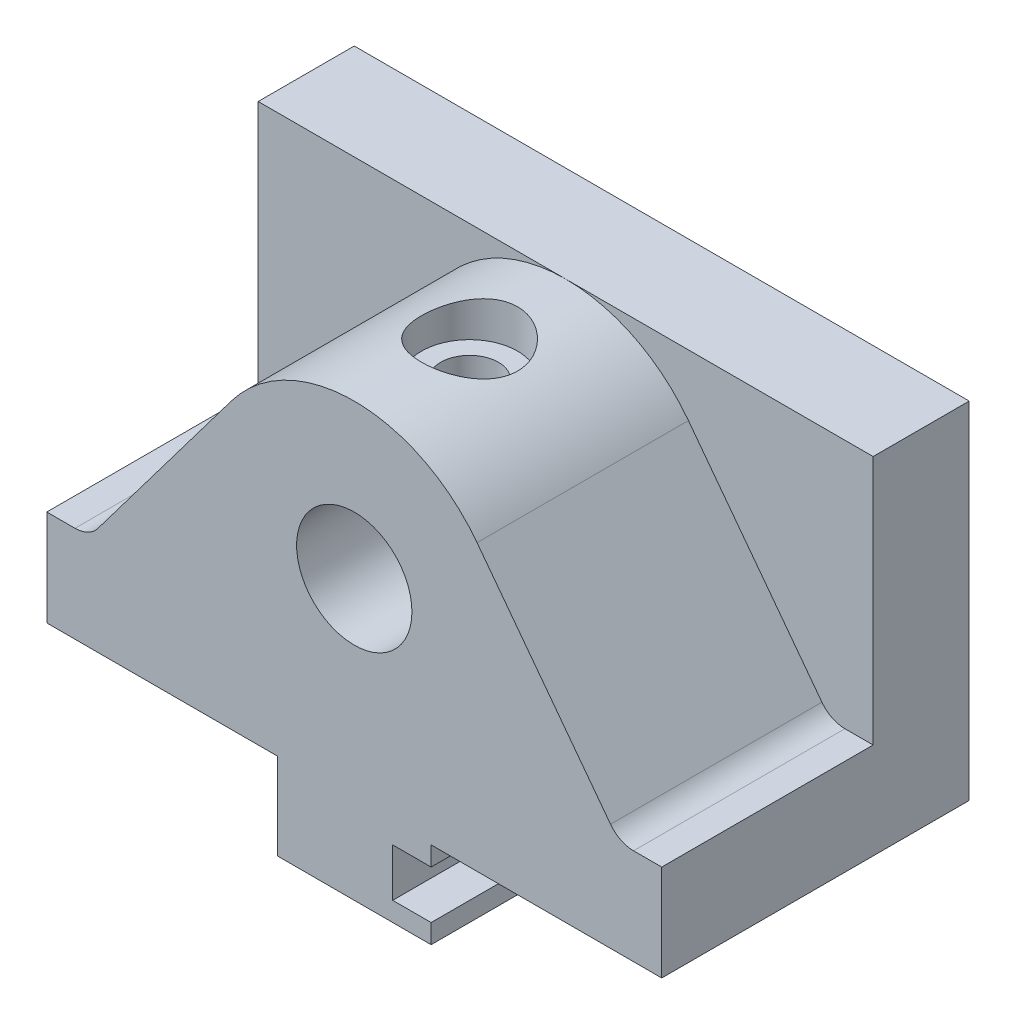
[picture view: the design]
ISO-10303-21;
HEADER;
FILE_DESCRIPTION(('STEP AP214'),'2;1');
FILE_NAME('part.step','',(''),(''),'','','');
FILE_SCHEMA(('AUTOMOTIVE_DESIGN { 1 0 10303 214 1 1 1 1 }'));
ENDSEC;
DATA;
#1=APPLICATION_CONTEXT('core data for automotive mechanical design processes');
#2=APPLICATION_PROTOCOL_DEFINITION('international standard','automotive_design',2000,#1);
#3=PRODUCT_CONTEXT('',#1,'mechanical');
#4=PRODUCT('Part','Part','',(#3));
#5=PRODUCT_RELATED_PRODUCT_CATEGORY('part','',(#4));
#6=PRODUCT_DEFINITION_FORMATION('','',#4);
#7=PRODUCT_DEFINITION_CONTEXT('part definition',#1,'design');
#8=PRODUCT_DEFINITION('design','',#6,#7);
#9=PRODUCT_DEFINITION_SHAPE('','',#8);
#10=(LENGTH_UNIT() NAMED_UNIT(*) SI_UNIT(.MILLI.,.METRE.));
#11=(NAMED_UNIT(*) PLANE_ANGLE_UNIT() SI_UNIT($,.RADIAN.));
#12=(NAMED_UNIT(*) SI_UNIT($,.STERADIAN.) SOLID_ANGLE_UNIT());
#13=UNCERTAINTY_MEASURE_WITH_UNIT(LENGTH_MEASURE(1.E-05),#10,'distance_accuracy_value','');
#14=(GEOMETRIC_REPRESENTATION_CONTEXT(3) GLOBAL_UNCERTAINTY_ASSIGNED_CONTEXT((#13)) GLOBAL_UNIT_ASSIGNED_CONTEXT((#10,
#11,#12)) REPRESENTATION_CONTEXT('',''));
#15=CARTESIAN_POINT('',(0.,0.,0.));
#16=DIRECTION('',(0.,0.,1.));
#17=DIRECTION('',(1.,0.,0.));
#18=AXIS2_PLACEMENT_3D('',#15,#16,#17);
#19=CARTESIAN_POINT('',(8.,-9.,22.));
#20=DIRECTION('',(-1.,0.,0.));
#21=DIRECTION('',(0.,-1.,0.));
#22=AXIS2_PLACEMENT_3D('',#19,#20,#21);
#23=PLANE('',#22);
#24=DIRECTION('',(0.,-1.,0.));
#25=VECTOR('',#24,1.);
#26=CARTESIAN_POINT('',(7.99999999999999,-9.,-9.99999999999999));
#27=LINE('',#26,#25);
#28=CARTESIAN_POINT('',(7.99999999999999,-7.,-9.99999999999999));
#29=VERTEX_POINT('',#28);
#30=CARTESIAN_POINT('',(7.99999999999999,-9.,-9.99999999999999));
#31=VERTEX_POINT('',#30);
#32=EDGE_CURVE('E212',#29,#31,#27,.T.);
#33=ORIENTED_EDGE('',*,*,#32,.F.);
#34=DIRECTION('',(0.,0.,1.));
#35=VECTOR('',#34,1.);
#36=CARTESIAN_POINT('',(7.99999999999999,-7.,-9.99999999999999));
#37=LINE('',#36,#35);
#38=CARTESIAN_POINT('',(8.,-7.,22.));
#39=VERTEX_POINT('',#38);
#40=EDGE_CURVE('E439',#29,#39,#37,.T.);
#41=ORIENTED_EDGE('',*,*,#40,.T.);
#42=DIRECTION('',(0.,1.,0.));
#43=VECTOR('',#42,1.);
#44=CARTESIAN_POINT('',(8.,-9.,22.));
#45=LINE('',#44,#43);
#46=CARTESIAN_POINT('',(8.,-9.,22.));
#47=VERTEX_POINT('',#46);
#48=EDGE_CURVE('E250',#47,#39,#45,.T.);
#49=ORIENTED_EDGE('',*,*,#48,.F.);
#50=DIRECTION('',(0.,0.,-1.));
#51=VECTOR('',#50,1.);
#52=CARTESIAN_POINT('',(8.,-9.,22.));
#53=LINE('',#52,#51);
#54=EDGE_CURVE('E358',#47,#31,#53,.T.);
#55=ORIENTED_EDGE('',*,*,#54,.T.);
#56=EDGE_LOOP('',(#33,#41,#49,#55));
#57=FACE_BOUND('',#56,.T.);
#58=ADVANCED_FACE('F34',(#57),#23,.F.);
#59=CARTESIAN_POINT('',(-8.,0.,22.));
#60=DIRECTION('',(1.,0.,0.));
#61=DIRECTION('',(0.,1.,0.));
#62=AXIS2_PLACEMENT_3D('',#59,#60,#61);
#63=PLANE('',#62);
#64=DIRECTION('',(0.,0.,-1.));
#65=VECTOR('',#64,1.);
#66=CARTESIAN_POINT('',(-8.,0.,22.));
#67=LINE('',#66,#65);
#68=CARTESIAN_POINT('',(-8.,0.,22.));
#69=VERTEX_POINT('',#68);
#70=CARTESIAN_POINT('',(-8.,0.,-10.));
#71=VERTEX_POINT('',#70);
#72=EDGE_CURVE('E272',#69,#71,#67,.T.);
#73=ORIENTED_EDGE('',*,*,#72,.T.);
#74=DIRECTION('',(0.,1.,0.));
#75=VECTOR('',#74,1.);
#76=CARTESIAN_POINT('',(-8.,0.,-10.));
#77=LINE('',#76,#75);
#78=CARTESIAN_POINT('',(-8.00000000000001,-9.,-10.));
#79=VERTEX_POINT('',#78);
#80=EDGE_CURVE('E215',#79,#71,#77,.T.);
#81=ORIENTED_EDGE('',*,*,#80,.F.);
#82=DIRECTION('',(0.,0.,-1.));
#83=VECTOR('',#82,1.);
#84=CARTESIAN_POINT('',(-8.,-9.,22.));
#85=LINE('',#84,#83);
#86=CARTESIAN_POINT('',(-8.,-9.,22.));
#87=VERTEX_POINT('',#86);
#88=EDGE_CURVE('E295',#87,#79,#85,.T.);
#89=ORIENTED_EDGE('',*,*,#88,.F.);
#90=DIRECTION('',(0.,-1.,0.));
#91=VECTOR('',#90,1.);
#92=CARTESIAN_POINT('',(-8.,0.,22.));
#93=LINE('',#92,#91);
#94=EDGE_CURVE('E244',#69,#87,#93,.T.);
#95=ORIENTED_EDGE('',*,*,#94,.F.);
#96=EDGE_LOOP('',(#73,#81,#89,#95));
#97=FACE_BOUND('',#96,.T.);
#98=ADVANCED_FACE('F372',(#97),#63,.F.);
#99=CARTESIAN_POINT('',(-8.,-9.,22.));
#100=DIRECTION('',(0.,1.,0.));
#101=DIRECTION('',(0.,0.,1.));
#102=AXIS2_PLACEMENT_3D('',#99,#100,#101);
#103=PLANE('',#102);
#104=CARTESIAN_POINT('',(0.,-9.,14.));
#105=DIRECTION('',(0.,-1.,0.));
#106=DIRECTION('',(0.,0.,-1.));
#107=AXIS2_PLACEMENT_3D('',#104,#105,#106);
#108=CIRCLE('',#107,2.99999999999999);
#109=CARTESIAN_POINT('',(0.,-9.,11.));
#110=VERTEX_POINT('',#109);
#111=EDGE_CURVE('E463',#110,#110,#108,.T.);
#112=ORIENTED_EDGE('',*,*,#111,.F.);
#113=EDGE_LOOP('',(#112));
#114=FACE_BOUND('',#113,.T.);
#115=CARTESIAN_POINT('',(0.,-9.,-2.));
#116=DIRECTION('',(0.,-1.,0.));
#117=DIRECTION('',(0.,0.,-1.));
#118=AXIS2_PLACEMENT_3D('',#115,#116,#117);
#119=CIRCLE('',#118,2.99999999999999);
#120=CARTESIAN_POINT('',(0.,-9.,-4.99999999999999));
#121=VERTEX_POINT('',#120);
#122=EDGE_CURVE('E740',#121,#121,#119,.T.);
#123=ORIENTED_EDGE('',*,*,#122,.F.);
#124=EDGE_LOOP('',(#123));
#125=FACE_BOUND('',#124,.T.);
#126=ORIENTED_EDGE('',*,*,#88,.T.);
#127=DIRECTION('',(-1.,0.,0.));
#128=VECTOR('',#127,1.);
#129=CARTESIAN_POINT('',(-8.00000000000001,-9.,-10.));
#130=LINE('',#129,#128);
#131=EDGE_CURVE('E211',#31,#79,#130,.T.);
#132=ORIENTED_EDGE('',*,*,#131,.F.);
#133=ORIENTED_EDGE('',*,*,#54,.F.);
#134=DIRECTION('',(1.,0.,0.));
#135=VECTOR('',#134,1.);
#136=CARTESIAN_POINT('',(-8.,-9.,22.));
#137=LINE('',#136,#135);
#138=EDGE_CURVE('E247',#87,#47,#137,.T.);
#139=ORIENTED_EDGE('',*,*,#138,.F.);
#140=EDGE_LOOP('',(#126,#132,#133,#139));
#141=FACE_BOUND('',#140,.T.);
#142=ADVANCED_FACE('F367',(#114,#125,#141),#103,.F.);
#143=CARTESIAN_POINT('',(8.,-2.,22.));
#144=VERTEX_POINT('',#143);
#145=CARTESIAN_POINT('',(8.00000000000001,0.,22.));
#146=VERTEX_POINT('',#145);
#147=EDGE_CURVE('E204',#144,#146,#45,.T.);
#148=ORIENTED_EDGE('',*,*,#147,.F.);
#149=DIRECTION('',(0.,0.,1.));
#150=VECTOR('',#149,1.);
#151=CARTESIAN_POINT('',(7.99999999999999,-2.,-9.99999999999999));
#152=LINE('',#151,#150);
#153=CARTESIAN_POINT('',(7.99999999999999,-2.,-9.99999999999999));
#154=VERTEX_POINT('',#153);
#155=EDGE_CURVE('E190',#154,#144,#152,.T.);
#156=ORIENTED_EDGE('',*,*,#155,.F.);
#157=CARTESIAN_POINT('',(8.00000000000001,0.,-9.99999999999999));
#158=VERTEX_POINT('',#157);
#159=EDGE_CURVE('E202',#158,#154,#27,.T.);
#160=ORIENTED_EDGE('',*,*,#159,.F.);
#161=DIRECTION('',(0.,0.,-1.));
#162=VECTOR('',#161,1.);
#163=CARTESIAN_POINT('',(8.00000000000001,0.,22.));
#164=LINE('',#163,#162);
#165=EDGE_CURVE('E357',#146,#158,#164,.T.);
#166=ORIENTED_EDGE('',*,*,#165,.F.);
#167=EDGE_LOOP('',(#148,#156,#160,#166));
#168=FACE_BOUND('',#167,.T.);
#169=ADVANCED_FACE('F200',(#168),#23,.F.);
#170=CARTESIAN_POINT('',(8.00000000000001,0.,22.));
#171=DIRECTION('',(0.,1.,0.));
#172=DIRECTION('',(0.,0.,1.));
#173=AXIS2_PLACEMENT_3D('',#170,#171,#172);
#174=PLANE('',#173);
#175=ORIENTED_EDGE('',*,*,#165,.T.);
#176=DIRECTION('',(-1.,0.,0.));
#177=VECTOR('',#176,1.);
#178=CARTESIAN_POINT('',(8.00000000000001,0.,-9.99999999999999));
#179=LINE('',#178,#177);
#180=CARTESIAN_POINT('',(32.,0.,-9.99999999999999));
#181=VERTEX_POINT('',#180);
#182=EDGE_CURVE('E210',#181,#158,#179,.T.);
#183=ORIENTED_EDGE('',*,*,#182,.F.);
#184=DIRECTION('',(0.,0.,-1.));
#185=VECTOR('',#184,1.);
#186=CARTESIAN_POINT('',(32.,0.,22.));
#187=LINE('',#186,#185);
#188=CARTESIAN_POINT('',(32.,0.,22.));
#189=VERTEX_POINT('',#188);
#190=EDGE_CURVE('E339',#189,#181,#187,.T.);
#191=ORIENTED_EDGE('',*,*,#190,.F.);
#192=DIRECTION('',(1.,0.,0.));
#193=VECTOR('',#192,1.);
#194=CARTESIAN_POINT('',(8.00000000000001,0.,22.));
#195=LINE('',#194,#193);
#196=EDGE_CURVE('E253',#146,#189,#195,.T.);
#197=ORIENTED_EDGE('',*,*,#196,.F.);
#198=EDGE_LOOP('',(#175,#183,#191,#197));
#199=FACE_BOUND('',#198,.T.);
#200=ADVANCED_FACE('F390',(#199),#174,.F.);
#201=CARTESIAN_POINT('',(32.,0.,22.));
#202=DIRECTION('',(-1.,0.,0.));
#203=DIRECTION('',(0.,0.,1.));
#204=AXIS2_PLACEMENT_3D('',#201,#202,#203);
#205=PLANE('',#204);
#206=ORIENTED_EDGE('',*,*,#190,.T.);
#207=DIRECTION('',(0.,-1.,0.));
#208=VECTOR('',#207,1.);
#209=CARTESIAN_POINT('',(32.,36.,-9.99999999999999));
#210=LINE('',#209,#208);
#211=CARTESIAN_POINT('',(32.,36.,-9.99999999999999));
#212=VERTEX_POINT('',#211);
#213=EDGE_CURVE('E229',#212,#181,#210,.T.);
#214=ORIENTED_EDGE('',*,*,#213,.F.);
#215=DIRECTION('',(0.,0.,1.));
#216=VECTOR('',#215,1.);
#217=CARTESIAN_POINT('',(32.,36.,-9.99999999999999));
#218=LINE('',#217,#216);
#219=CARTESIAN_POINT('',(32.,36.,0.));
#220=VERTEX_POINT('',#219);
#221=EDGE_CURVE('E231',#212,#220,#218,.T.);
#222=ORIENTED_EDGE('',*,*,#221,.T.);
#223=DIRECTION('',(0.,-1.,0.));
#224=VECTOR('',#223,1.);
#225=CARTESIAN_POINT('',(32.,0.,0.));
#226=LINE('',#225,#224);
#227=CARTESIAN_POINT('',(32.,10.,0.));
#228=VERTEX_POINT('',#227);
#229=EDGE_CURVE('E242',#220,#228,#226,.T.);
#230=ORIENTED_EDGE('',*,*,#229,.T.);
#231=DIRECTION('',(0.,0.,-1.));
#232=VECTOR('',#231,1.);
#233=CARTESIAN_POINT('',(32.,10.,22.));
#234=LINE('',#233,#232);
#235=CARTESIAN_POINT('',(32.,10.,22.));
#236=VERTEX_POINT('',#235);
#237=EDGE_CURVE('E329',#236,#228,#234,.T.);
#238=ORIENTED_EDGE('',*,*,#237,.F.);
#239=DIRECTION('',(0.,1.,0.));
#240=VECTOR('',#239,1.);
#241=CARTESIAN_POINT('',(32.,0.,22.));
#242=LINE('',#241,#240);
#243=EDGE_CURVE('E255',#189,#236,#242,.T.);
#244=ORIENTED_EDGE('',*,*,#243,.F.);
#245=EDGE_LOOP('',(#206,#214,#222,#230,#238,#244));
#246=FACE_BOUND('',#245,.T.);
#247=ADVANCED_FACE('F394',(#246),#205,.F.);
#248=CARTESIAN_POINT('',(32.,10.,22.));
#249=DIRECTION('',(0.,-1.,0.));
#250=DIRECTION('',(1.,0.,0.));
#251=AXIS2_PLACEMENT_3D('',#248,#249,#250);
#252=PLANE('',#251);
#253=DIRECTION('',(-1.,0.,0.));
#254=VECTOR('',#253,1.);
#255=CARTESIAN_POINT('',(32.,10.,0.));
#256=LINE('',#255,#254);
#257=CARTESIAN_POINT('',(29.0654558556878,9.99999999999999,0.));
#258=VERTEX_POINT('',#257);
#259=EDGE_CURVE('E276',#228,#258,#256,.T.);
#260=ORIENTED_EDGE('',*,*,#259,.T.);
#261=DIRECTION('',(0.,0.,-1.));
#262=VECTOR('',#261,1.);
#263=CARTESIAN_POINT('',(29.0654558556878,9.99999999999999,22.));
#264=LINE('',#263,#262);
#265=CARTESIAN_POINT('',(29.0654558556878,9.99999999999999,22.));
#266=VERTEX_POINT('',#265);
#267=EDGE_CURVE('E62',#258,#266,#264,.F.);
#268=ORIENTED_EDGE('',*,*,#267,.T.);
#269=DIRECTION('',(-1.,0.,0.));
#270=VECTOR('',#269,1.);
#271=CARTESIAN_POINT('',(32.,10.,22.));
#272=LINE('',#271,#270);
#273=EDGE_CURVE('E257',#236,#266,#272,.T.);
#274=ORIENTED_EDGE('',*,*,#273,.F.);
#275=ORIENTED_EDGE('',*,*,#237,.T.);
#276=EDGE_LOOP('',(#260,#268,#274,#275));
#277=FACE_BOUND('',#276,.T.);
#278=ADVANCED_FACE('F327',(#277),#252,.F.);
#279=CARTESIAN_POINT('',(27.5697110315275,9.99999999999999,22.));
#280=DIRECTION('',(-0.798635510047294,-0.601815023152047,0.));
#281=DIRECTION('',(0.601815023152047,-0.798635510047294,0.));
#282=AXIS2_PLACEMENT_3D('',#279,#280,#281);
#283=PLANE('',#282);
#284=DIRECTION('',(-0.601815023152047,0.798635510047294,0.));
#285=VECTOR('',#284,1.);
#286=CARTESIAN_POINT('',(27.5697110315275,9.99999999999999,22.));
#287=LINE('',#286,#285);
#288=CARTESIAN_POINT('',(26.6695493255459,11.1945549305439,22.));
#289=VERTEX_POINT('',#288);
#290=CARTESIAN_POINT('',(12.7781681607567,29.6290403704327,22.));
#291=VERTEX_POINT('',#290);
#292=EDGE_CURVE('E259',#289,#291,#287,.T.);
#293=ORIENTED_EDGE('',*,*,#292,.F.);
#294=DIRECTION('',(0.,0.,-1.));
#295=VECTOR('',#294,1.);
#296=CARTESIAN_POINT('',(26.6695493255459,11.1945549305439,0.));
#297=LINE('',#296,#295);
#298=CARTESIAN_POINT('',(26.6695493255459,11.1945549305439,0.));
#299=VERTEX_POINT('',#298);
#300=EDGE_CURVE('E299',#289,#299,#297,.T.);
#301=ORIENTED_EDGE('',*,*,#300,.T.);
#302=DIRECTION('',(-0.601815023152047,0.798635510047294,0.));
#303=VECTOR('',#302,1.);
#304=CARTESIAN_POINT('',(27.5697110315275,9.99999999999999,0.));
#305=LINE('',#304,#303);
#306=CARTESIAN_POINT('',(12.7781681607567,29.6290403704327,0.));
#307=VERTEX_POINT('',#306);
#308=EDGE_CURVE('E273',#299,#307,#305,.T.);
#309=ORIENTED_EDGE('',*,*,#308,.T.);
#310=DIRECTION('',(0.,0.,-1.));
#311=VECTOR('',#310,1.);
#312=CARTESIAN_POINT('',(12.7781681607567,29.6290403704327,22.));
#313=LINE('',#312,#311);
#314=EDGE_CURVE('E319',#291,#307,#313,.T.);
#315=ORIENTED_EDGE('',*,*,#314,.F.);
#316=EDGE_LOOP('',(#293,#301,#309,#315));
#317=FACE_BOUND('',#316,.T.);
#318=ADVANCED_FACE('F316',(#317),#283,.F.);
#319=CARTESIAN_POINT('',(0.,20.,22.));
#320=DIRECTION('',(0.,0.,-1.));
#321=DIRECTION('',(-1.,0.,0.));
#322=AXIS2_PLACEMENT_3D('',#319,#320,#321);
#323=CYLINDRICAL_SURFACE('',#322,16.);
#324=CARTESIAN_POINT('',(0.,36.,15.));
#325=CARTESIAN_POINT('',(-0.273756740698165,35.9999986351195,14.9999982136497));
#326=CARTESIAN_POINT('',(-0.547532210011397,35.9929077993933,14.9774430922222));
#327=CARTESIAN_POINT('',(-1.08707683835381,35.9653157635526,14.888055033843));
#328=CARTESIAN_POINT('',(-1.35284417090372,35.9448115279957,14.8212120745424));
#329=CARTESIAN_POINT('',(-1.86851417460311,35.892632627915,14.6457225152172));
#330=CARTESIAN_POINT('',(-2.11844070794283,35.860975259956,14.5371406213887));
#331=CARTESIAN_POINT('',(-2.59653920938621,35.7897587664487,14.2815307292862));
#332=CARTESIAN_POINT('',(-2.82470774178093,35.7501983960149,14.1344966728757));
#333=CARTESIAN_POINT('',(-3.25986133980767,35.6660085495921,13.8013760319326));
#334=CARTESIAN_POINT('',(-3.46608011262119,35.621268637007,13.6143164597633));
#335=CARTESIAN_POINT('',(-3.84478952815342,35.5324018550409,13.2085264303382));
#336=CARTESIAN_POINT('',(-4.01727389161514,35.4882751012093,12.9897900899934));
#337=CARTESIAN_POINT('',(-4.32777345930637,35.4044457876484,12.5202217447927));
#338=CARTESIAN_POINT('',(-4.4648313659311,35.364879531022,12.2687300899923));
#339=CARTESIAN_POINT('',(-4.69438964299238,35.2963120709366,11.7448307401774));
#340=CARTESIAN_POINT('',(-4.78690175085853,35.2673080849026,11.4724285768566));
#341=CARTESIAN_POINT('',(-4.92193839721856,35.224304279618,10.9230876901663));
#342=CARTESIAN_POINT('',(-4.96588440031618,35.2098789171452,10.6465326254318));
#343=CARTESIAN_POINT('',(-5.00698220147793,35.1964022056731,10.0896275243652));
#344=CARTESIAN_POINT('',(-5.00414643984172,35.1973467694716,9.80927851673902));
#345=CARTESIAN_POINT('',(-4.95287298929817,35.2141275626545,9.26450215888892));
#346=CARTESIAN_POINT('',(-4.90624231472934,35.2293736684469,8.99988349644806));
#347=CARTESIAN_POINT('',(-4.7716325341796,35.272081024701,8.48243137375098));
#348=CARTESIAN_POINT('',(-4.68364903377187,35.2995435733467,8.22959916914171));
#349=CARTESIAN_POINT('',(-4.46755498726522,35.3640417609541,7.73859222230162));
#350=CARTESIAN_POINT('',(-4.33887702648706,35.4012113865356,7.5006855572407));
#351=CARTESIAN_POINT('',(-4.04544082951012,35.4808742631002,7.04924892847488));
#352=CARTESIAN_POINT('',(-3.88067322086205,35.523368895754,6.83572531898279));
#353=CARTESIAN_POINT('',(-3.51086781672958,35.6112611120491,6.42890022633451));
#354=CARTESIAN_POINT('',(-3.30433828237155,35.6567027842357,6.23696176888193));
#355=CARTESIAN_POINT('',(-2.86145763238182,35.7436628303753,5.89011242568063));
#356=CARTESIAN_POINT('',(-2.625104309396,35.7851809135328,5.735204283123));
#357=CARTESIAN_POINT('',(-2.12665844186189,35.8600517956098,5.46588924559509));
#358=CARTESIAN_POINT('',(-1.86437962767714,35.8933384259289,5.35180745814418));
#359=CARTESIAN_POINT('',(-1.32307191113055,35.9475182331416,5.1697879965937));
#360=CARTESIAN_POINT('',(-1.04404812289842,35.9684151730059,5.10183631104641));
#361=CARTESIAN_POINT('',(-0.488740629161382,35.9948555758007,5.0163278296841));
#362=CARTESIAN_POINT('',(-0.212767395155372,36.0009609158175,4.99692582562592));
#363=CARTESIAN_POINT('',(0.338521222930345,35.9987919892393,5.00386490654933));
#364=CARTESIAN_POINT('',(0.613836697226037,35.9905198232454,5.03019930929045));
#365=CARTESIAN_POINT('',(1.14887733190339,35.9608945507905,5.12638237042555));
#366=CARTESIAN_POINT('',(1.40881991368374,35.9398717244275,5.19513307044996));
#367=CARTESIAN_POINT('',(1.9134077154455,35.8872048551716,5.37285740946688));
#368=CARTESIAN_POINT('',(2.15805104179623,35.8555595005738,5.48183601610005));
#369=CARTESIAN_POINT('',(2.63172962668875,35.783941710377,5.73989286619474));
#370=CARTESIAN_POINT('',(2.86023895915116,35.7437850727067,5.88988394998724));
#371=CARTESIAN_POINT('',(3.28946340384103,35.6597364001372,6.22461284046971));
#372=CARTESIAN_POINT('',(3.49017095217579,35.6158433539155,6.40936007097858));
#373=CARTESIAN_POINT('',(3.86634985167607,35.5270797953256,6.8170355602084));
#374=CARTESIAN_POINT('',(4.04050609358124,35.4822394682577,7.0411866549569));
#375=CARTESIAN_POINT('',(4.34885000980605,35.3984778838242,7.51650646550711));
#376=CARTESIAN_POINT('',(4.48303831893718,35.3595565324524,7.76767475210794));
#377=CARTESIAN_POINT('',(4.70680333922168,35.2924712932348,8.28938069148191));
#378=CARTESIAN_POINT('',(4.79655278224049,35.264265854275,8.55983859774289));
#379=CARTESIAN_POINT('',(4.9289157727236,35.2220468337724,9.11308997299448));
#380=CARTESIAN_POINT('',(4.97154725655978,35.2080278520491,9.39587870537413));
#381=CARTESIAN_POINT('',(5.00717624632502,35.1963317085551,9.95201635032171));
#382=CARTESIAN_POINT('',(5.00233118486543,35.1979441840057,10.2252138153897));
#383=CARTESIAN_POINT('',(4.94835272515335,35.2156036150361,10.7666983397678));
#384=CARTESIAN_POINT('',(4.89922139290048,35.2316498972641,11.0349856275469));
#385=CARTESIAN_POINT('',(4.7595091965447,35.2758725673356,11.5551761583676));
#386=CARTESIAN_POINT('',(4.66954569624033,35.3038679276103,11.8072617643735));
#387=CARTESIAN_POINT('',(4.45120909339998,35.3687881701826,12.292961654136));
#388=CARTESIAN_POINT('',(4.32282817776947,35.4057148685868,12.5265721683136));
#389=CARTESIAN_POINT('',(4.02542700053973,35.4861394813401,12.9785838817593));
#390=CARTESIAN_POINT('',(3.85501334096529,35.5298379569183,13.196032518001));
#391=CARTESIAN_POINT('',(3.4808359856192,35.6179599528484,13.599945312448));
#392=CARTESIAN_POINT('',(3.27706336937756,35.6623836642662,13.7864011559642));
#393=CARTESIAN_POINT('',(2.83394665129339,35.7486908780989,14.1291301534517));
#394=CARTESIAN_POINT('',(2.59365829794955,35.7904440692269,14.2842189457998));
#395=CARTESIAN_POINT('',(2.08911655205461,35.8650707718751,14.5515956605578));
#396=CARTESIAN_POINT('',(1.8248726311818,35.8979477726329,14.6639004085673));
#397=CARTESIAN_POINT('',(1.30299054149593,35.9488260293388,14.8343654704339));
#398=CARTESIAN_POINT('',(1.0466813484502,35.9678496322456,14.8962994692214));
#399=CARTESIAN_POINT('',(0.526919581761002,35.9934360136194,14.9791134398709));
#400=CARTESIAN_POINT('',(0.263468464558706,36.0000013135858,15.000001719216));
#401=CARTESIAN_POINT('',(0.,36.,15.));
#402=B_SPLINE_CURVE_WITH_KNOTS('',3,(#324,#325,#326,#327,#328,#329,#330,#331,#332,#333,#334,
#335,#336,#337,#338,#339,#340,#341,#342,#343,#344,#345,#346,#347,#348,#349,#350,#351,#352,#353,
#354,#355,#356,#357,#358,#359,#360,#361,#362,#363,#364,#365,#366,#367,#368,#369,#370,#371,#372,
#373,#374,#375,#376,#377,#378,#379,#380,#381,#382,#383,#384,#385,#386,#387,#388,#389,#390,#391,
#392,#393,#394,#395,#396,#397,#398,#399,#400,#401),.UNSPECIFIED.,.T.,.F.,(4,2,2,2,2,2,2,2,2,2,2,
2,2,2,2,2,2,2,2,2,2,2,2,2,2,2,2,2,2,2,2,2,2,2,2,2,2,2,4),(0.,0.820301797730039,1.64078929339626,
2.46000991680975,3.27935968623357,4.12151288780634,4.96382269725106,5.82695084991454,
6.68985145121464,7.52676600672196,8.36345801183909,9.16707669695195,9.97078079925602,
10.7862257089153,11.6018826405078,12.4546698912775,13.3075202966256,14.1670184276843,
15.0262553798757,15.852302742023,16.678229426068,17.4836250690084,18.2891202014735,
19.1142529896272,19.9396098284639,20.7976711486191,21.655718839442,22.5104046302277,
23.3647649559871,24.1804881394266,24.9961732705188,25.7999165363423,26.6038233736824,
27.4391805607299,28.274761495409,29.1376267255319,30.0001522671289,30.789785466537,
31.5792588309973),.UNSPECIFIED.);
#403=CARTESIAN_POINT('',(0.,36.,15.));
#404=VERTEX_POINT('',#403);
#405=EDGE_CURVE('E11',#404,#404,#402,.T.);
#406=ORIENTED_EDGE('',*,*,#405,.T.);
#407=EDGE_LOOP('',(#406));
#408=FACE_BOUND('',#407,.T.);
#409=CARTESIAN_POINT('',(0.,20.,0.));
#410=DIRECTION('',(0.,0.,1.));
#411=DIRECTION('',(1.,0.,0.));
#412=AXIS2_PLACEMENT_3D('',#409,#410,#411);
#413=CIRCLE('',#412,16.);
#414=CARTESIAN_POINT('',(0.,36.,0.));
#415=VERTEX_POINT('',#414);
#416=EDGE_CURVE('E277',#307,#415,#413,.T.);
#417=ORIENTED_EDGE('',*,*,#416,.T.);
#418=CARTESIAN_POINT('',(-12.7781681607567,29.6290403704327,0.));
#419=VERTEX_POINT('',#418);
#420=EDGE_CURVE('E275',#415,#419,#413,.T.);
#421=ORIENTED_EDGE('',*,*,#420,.T.);
#422=DIRECTION('',(0.,0.,-1.));
#423=VECTOR('',#422,1.);
#424=CARTESIAN_POINT('',(-12.7781681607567,29.6290403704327,22.));
#425=LINE('',#424,#423);
#426=CARTESIAN_POINT('',(-12.7781681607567,29.6290403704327,22.));
#427=VERTEX_POINT('',#426);
#428=EDGE_CURVE('E343',#427,#419,#425,.T.);
#429=ORIENTED_EDGE('',*,*,#428,.F.);
#430=CARTESIAN_POINT('',(0.,20.,22.));
#431=DIRECTION('',(0.,0.,1.));
#432=DIRECTION('',(1.,0.,0.));
#433=AXIS2_PLACEMENT_3D('',#430,#431,#432);
#434=CIRCLE('',#433,16.);
#435=EDGE_CURVE('E261',#291,#427,#434,.T.);
#436=ORIENTED_EDGE('',*,*,#435,.F.);
#437=ORIENTED_EDGE('',*,*,#314,.T.);
#438=EDGE_LOOP('',(#417,#421,#429,#436,#437));
#439=FACE_BOUND('',#438,.T.);
#440=ADVANCED_FACE('F566',(#408,#439),#323,.T.);
#441=CARTESIAN_POINT('',(-12.7781681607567,29.6290403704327,22.));
#442=DIRECTION('',(0.798635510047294,-0.601815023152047,0.));
#443=DIRECTION('',(0.601815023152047,0.798635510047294,0.));
#444=AXIS2_PLACEMENT_3D('',#441,#442,#443);
#445=PLANE('',#444);
#446=DIRECTION('',(-0.601815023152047,-0.798635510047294,0.));
#447=VECTOR('',#446,1.);
#448=CARTESIAN_POINT('',(-12.7781681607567,29.6290403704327,0.));
#449=LINE('',#448,#447);
#450=CARTESIAN_POINT('',(-26.6695493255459,11.1945549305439,0.));
#451=VERTEX_POINT('',#450);
#452=EDGE_CURVE('E280',#419,#451,#449,.T.);
#453=ORIENTED_EDGE('',*,*,#452,.T.);
#454=DIRECTION('',(0.,0.,-1.));
#455=VECTOR('',#454,1.);
#456=CARTESIAN_POINT('',(-26.6695493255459,11.1945549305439,22.));
#457=LINE('',#456,#455);
#458=CARTESIAN_POINT('',(-26.6695493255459,11.1945549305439,22.));
#459=VERTEX_POINT('',#458);
#460=EDGE_CURVE('E297',#451,#459,#457,.F.);
#461=ORIENTED_EDGE('',*,*,#460,.T.);
#462=DIRECTION('',(-0.601815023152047,-0.798635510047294,0.));
#463=VECTOR('',#462,1.);
#464=CARTESIAN_POINT('',(-12.7781681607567,29.6290403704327,22.));
#465=LINE('',#464,#463);
#466=EDGE_CURVE('E263',#427,#459,#465,.T.);
#467=ORIENTED_EDGE('',*,*,#466,.F.);
#468=ORIENTED_EDGE('',*,*,#428,.T.);
#469=EDGE_LOOP('',(#453,#461,#467,#468));
#470=FACE_BOUND('',#469,.T.);
#471=ADVANCED_FACE('F575',(#470),#445,.F.);
#472=CARTESIAN_POINT('',(-27.5697110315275,9.99999999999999,22.));
#473=DIRECTION('',(0.,-1.,0.));
#474=DIRECTION('',(1.,0.,0.));
#475=AXIS2_PLACEMENT_3D('',#472,#473,#474);
#476=PLANE('',#475);
#477=DIRECTION('',(-1.,0.,0.));
#478=VECTOR('',#477,1.);
#479=CARTESIAN_POINT('',(-27.5697110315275,9.99999999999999,22.));
#480=LINE('',#479,#478);
#481=CARTESIAN_POINT('',(-29.0654558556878,9.99999999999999,22.));
#482=VERTEX_POINT('',#481);
#483=CARTESIAN_POINT('',(-32.,10.,22.));
#484=VERTEX_POINT('',#483);
#485=EDGE_CURVE('E266',#482,#484,#480,.T.);
#486=ORIENTED_EDGE('',*,*,#485,.F.);
#487=DIRECTION('',(0.,0.,-1.));
#488=VECTOR('',#487,1.);
#489=CARTESIAN_POINT('',(-29.0654558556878,9.99999999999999,0.));
#490=LINE('',#489,#488);
#491=CARTESIAN_POINT('',(-29.0654558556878,9.99999999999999,0.));
#492=VERTEX_POINT('',#491);
#493=EDGE_CURVE('E291',#482,#492,#490,.T.);
#494=ORIENTED_EDGE('',*,*,#493,.T.);
#495=DIRECTION('',(-1.,0.,0.));
#496=VECTOR('',#495,1.);
#497=CARTESIAN_POINT('',(-27.5697110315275,9.99999999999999,0.));
#498=LINE('',#497,#496);
#499=CARTESIAN_POINT('',(-32.,10.,0.));
#500=VERTEX_POINT('',#499);
#501=EDGE_CURVE('E248',#492,#500,#498,.T.);
#502=ORIENTED_EDGE('',*,*,#501,.T.);
#503=DIRECTION('',(0.,0.,-1.));
#504=VECTOR('',#503,1.);
#505=CARTESIAN_POINT('',(-32.,10.,22.));
#506=LINE('',#505,#504);
#507=EDGE_CURVE('E341',#484,#500,#506,.T.);
#508=ORIENTED_EDGE('',*,*,#507,.F.);
#509=EDGE_LOOP('',(#486,#494,#502,#508));
#510=FACE_BOUND('',#509,.T.);
#511=ADVANCED_FACE('F436',(#510),#476,.F.);
#512=CARTESIAN_POINT('',(-32.,10.,22.));
#513=DIRECTION('',(1.,0.,0.));
#514=DIRECTION('',(0.,0.,-1.));
#515=AXIS2_PLACEMENT_3D('',#512,#513,#514);
#516=PLANE('',#515);
#517=ORIENTED_EDGE('',*,*,#507,.T.);
#518=DIRECTION('',(0.,1.,0.));
#519=VECTOR('',#518,1.);
#520=CARTESIAN_POINT('',(-32.,36.,0.));
#521=LINE('',#520,#519);
#522=CARTESIAN_POINT('',(-32.,36.,0.));
#523=VERTEX_POINT('',#522);
#524=EDGE_CURVE('E237',#500,#523,#521,.T.);
#525=ORIENTED_EDGE('',*,*,#524,.T.);
#526=DIRECTION('',(0.,0.,1.));
#527=VECTOR('',#526,1.);
#528=CARTESIAN_POINT('',(-32.,36.,-9.99999999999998));
#529=LINE('',#528,#527);
#530=CARTESIAN_POINT('',(-32.,36.,-9.99999999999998));
#531=VERTEX_POINT('',#530);
#532=EDGE_CURVE('E330',#531,#523,#529,.T.);
#533=ORIENTED_EDGE('',*,*,#532,.F.);
#534=DIRECTION('',(0.,1.,0.));
#535=VECTOR('',#534,1.);
#536=CARTESIAN_POINT('',(-32.,10.,-9.99999999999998));
#537=LINE('',#536,#535);
#538=CARTESIAN_POINT('',(-32.,0.,-9.99999999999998));
#539=VERTEX_POINT('',#538);
#540=EDGE_CURVE('E225',#539,#531,#537,.T.);
#541=ORIENTED_EDGE('',*,*,#540,.F.);
#542=DIRECTION('',(0.,0.,-1.));
#543=VECTOR('',#542,1.);
#544=CARTESIAN_POINT('',(-32.,0.,22.));
#545=LINE('',#544,#543);
#546=CARTESIAN_POINT('',(-32.,0.,22.));
#547=VERTEX_POINT('',#546);
#548=EDGE_CURVE('E344',#547,#539,#545,.T.);
#549=ORIENTED_EDGE('',*,*,#548,.F.);
#550=DIRECTION('',(0.,-1.,0.));
#551=VECTOR('',#550,1.);
#552=CARTESIAN_POINT('',(-32.,10.,22.));
#553=LINE('',#552,#551);
#554=EDGE_CURVE('E268',#484,#547,#553,.T.);
#555=ORIENTED_EDGE('',*,*,#554,.F.);
#556=EDGE_LOOP('',(#517,#525,#533,#541,#549,#555));
#557=FACE_BOUND('',#556,.T.);
#558=ADVANCED_FACE('F377',(#557),#516,.F.);
#559=CARTESIAN_POINT('',(-32.,0.,22.));
#560=DIRECTION('',(0.,1.,0.));
#561=DIRECTION('',(0.,0.,1.));
#562=AXIS2_PLACEMENT_3D('',#559,#560,#561);
#563=PLANE('',#562);
#564=ORIENTED_EDGE('',*,*,#548,.T.);
#565=DIRECTION('',(-1.,0.,0.));
#566=VECTOR('',#565,1.);
#567=CARTESIAN_POINT('',(-32.,0.,-9.99999999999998));
#568=LINE('',#567,#566);
#569=EDGE_CURVE('E222',#71,#539,#568,.T.);
#570=ORIENTED_EDGE('',*,*,#569,.F.);
#571=ORIENTED_EDGE('',*,*,#72,.F.);
#572=DIRECTION('',(1.,0.,0.));
#573=VECTOR('',#572,1.);
#574=CARTESIAN_POINT('',(-32.,0.,22.));
#575=LINE('',#574,#573);
#576=EDGE_CURVE('E270',#547,#69,#575,.T.);
#577=ORIENTED_EDGE('',*,*,#576,.F.);
#578=EDGE_LOOP('',(#564,#570,#571,#577));
#579=FACE_BOUND('',#578,.T.);
#580=ADVANCED_FACE('F374',(#579),#563,.F.);
#581=CARTESIAN_POINT('',(0.,20.,22.));
#582=DIRECTION('',(0.,0.,1.));
#583=DIRECTION('',(1.,0.,0.));
#584=AXIS2_PLACEMENT_3D('',#581,#582,#583);
#585=PLANE('',#584);
#586=DIRECTION('',(1.,0.,0.));
#587=VECTOR('',#586,1.);
#588=CARTESIAN_POINT('',(8.,-7.,22.));
#589=LINE('',#588,#587);
#590=CARTESIAN_POINT('',(4.,-7.,22.));
#591=VERTEX_POINT('',#590);
#592=EDGE_CURVE('E195',#591,#39,#589,.T.);
#593=ORIENTED_EDGE('',*,*,#592,.F.);
#594=DIRECTION('',(0.,-1.,0.));
#595=VECTOR('',#594,1.);
#596=CARTESIAN_POINT('',(4.,-2.,22.));
#597=LINE('',#596,#595);
#598=CARTESIAN_POINT('',(4.,-2.,22.));
#599=VERTEX_POINT('',#598);
#600=EDGE_CURVE('E492',#599,#591,#597,.T.);
#601=ORIENTED_EDGE('',*,*,#600,.F.);
#602=DIRECTION('',(-1.,0.,0.));
#603=VECTOR('',#602,1.);
#604=CARTESIAN_POINT('',(8.,-2.,22.));
#605=LINE('',#604,#603);
#606=EDGE_CURVE('E493',#144,#599,#605,.T.);
#607=ORIENTED_EDGE('',*,*,#606,.F.);
#608=ORIENTED_EDGE('',*,*,#147,.T.);
#609=ORIENTED_EDGE('',*,*,#196,.T.);
#610=ORIENTED_EDGE('',*,*,#243,.T.);
#611=ORIENTED_EDGE('',*,*,#273,.T.);
#612=CARTESIAN_POINT('',(29.0654558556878,13.,22.));
#613=DIRECTION('',(0.,0.,1.));
#614=DIRECTION('',(1.,0.,0.));
#615=AXIS2_PLACEMENT_3D('',#612,#613,#614);
#616=CIRCLE('',#615,3.);
#617=EDGE_CURVE('E47',#266,#289,#616,.F.);
#618=ORIENTED_EDGE('',*,*,#617,.T.);
#619=ORIENTED_EDGE('',*,*,#292,.T.);
#620=ORIENTED_EDGE('',*,*,#435,.T.);
#621=ORIENTED_EDGE('',*,*,#466,.T.);
#622=CARTESIAN_POINT('',(-29.0654558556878,13.,22.));
#623=DIRECTION('',(0.,0.,1.));
#624=DIRECTION('',(1.,0.,0.));
#625=AXIS2_PLACEMENT_3D('',#622,#623,#624);
#626=CIRCLE('',#625,3.);
#627=EDGE_CURVE('E305',#459,#482,#626,.F.);
#628=ORIENTED_EDGE('',*,*,#627,.T.);
#629=ORIENTED_EDGE('',*,*,#485,.T.);
#630=ORIENTED_EDGE('',*,*,#554,.T.);
#631=ORIENTED_EDGE('',*,*,#576,.T.);
#632=ORIENTED_EDGE('',*,*,#94,.T.);
#633=ORIENTED_EDGE('',*,*,#138,.T.);
#634=ORIENTED_EDGE('',*,*,#48,.T.);
#635=EDGE_LOOP('',(#593,#601,#607,#608,#609,#610,#611,#618,#619,#620,#621,#628,#629,#630,#631,
#632,#633,#634));
#636=FACE_BOUND('',#635,.T.);
#637=CARTESIAN_POINT('',(0.,20.,22.));
#638=DIRECTION('',(0.,0.,1.));
#639=DIRECTION('',(1.,0.,0.));
#640=AXIS2_PLACEMENT_3D('',#637,#638,#639);
#641=CIRCLE('',#640,6.);
#642=CARTESIAN_POINT('',(6.00000000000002,20.,22.));
#643=VERTEX_POINT('',#642);
#644=EDGE_CURVE('E748',#643,#643,#641,.T.);
#645=ORIENTED_EDGE('',*,*,#644,.F.);
#646=EDGE_LOOP('',(#645));
#647=FACE_BOUND('',#646,.T.);
#648=ADVANCED_FACE('F310',(#636,#647),#585,.T.);
#649=CARTESIAN_POINT('',(32.,0.,0.));
#650=DIRECTION('',(0.,0.,1.));
#651=DIRECTION('',(1.,0.,0.));
#652=AXIS2_PLACEMENT_3D('',#649,#650,#651);
#653=PLANE('',#652);
#654=ORIENTED_EDGE('',*,*,#501,.F.);
#655=CARTESIAN_POINT('',(-29.0654558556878,13.,0.));
#656=DIRECTION('',(0.,0.,1.));
#657=DIRECTION('',(1.,0.,0.));
#658=AXIS2_PLACEMENT_3D('',#655,#656,#657);
#659=CIRCLE('',#658,3.);
#660=EDGE_CURVE('E294',#492,#451,#659,.T.);
#661=ORIENTED_EDGE('',*,*,#660,.T.);
#662=ORIENTED_EDGE('',*,*,#452,.F.);
#663=ORIENTED_EDGE('',*,*,#420,.F.);
#664=DIRECTION('',(1.,0.,0.));
#665=VECTOR('',#664,1.);
#666=CARTESIAN_POINT('',(32.,36.,0.));
#667=LINE('',#666,#665);
#668=EDGE_CURVE('E234',#523,#415,#667,.T.);
#669=ORIENTED_EDGE('',*,*,#668,.F.);
#670=ORIENTED_EDGE('',*,*,#524,.F.);
#671=EDGE_LOOP('',(#654,#661,#662,#663,#669,#670));
#672=FACE_BOUND('',#671,.T.);
#673=ADVANCED_FACE('F619',(#672),#653,.T.);
#674=ORIENTED_EDGE('',*,*,#308,.F.);
#675=CARTESIAN_POINT('',(29.0654558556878,13.,0.));
#676=DIRECTION('',(0.,0.,1.));
#677=DIRECTION('',(1.,0.,0.));
#678=AXIS2_PLACEMENT_3D('',#675,#676,#677);
#679=CIRCLE('',#678,3.);
#680=EDGE_CURVE('E302',#299,#258,#679,.T.);
#681=ORIENTED_EDGE('',*,*,#680,.T.);
#682=ORIENTED_EDGE('',*,*,#259,.F.);
#683=ORIENTED_EDGE('',*,*,#229,.F.);
#684=EDGE_CURVE('E240',#415,#220,#667,.T.);
#685=ORIENTED_EDGE('',*,*,#684,.F.);
#686=ORIENTED_EDGE('',*,*,#416,.F.);
#687=EDGE_LOOP('',(#674,#681,#682,#683,#685,#686));
#688=FACE_BOUND('',#687,.T.);
#689=ADVANCED_FACE('F322',(#688),#653,.T.);
#690=CARTESIAN_POINT('',(32.,36.,-9.99999999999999));
#691=DIRECTION('',(0.,-1.,0.));
#692=DIRECTION('',(0.,0.,-1.));
#693=AXIS2_PLACEMENT_3D('',#690,#691,#692);
#694=PLANE('',#693);
#695=ORIENTED_EDGE('',*,*,#668,.T.);
#696=ORIENTED_EDGE('',*,*,#684,.T.);
#697=ORIENTED_EDGE('',*,*,#221,.F.);
#698=DIRECTION('',(1.,0.,0.));
#699=VECTOR('',#698,1.);
#700=CARTESIAN_POINT('',(32.,36.,-9.99999999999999));
#701=LINE('',#700,#699);
#702=EDGE_CURVE('E227',#531,#212,#701,.T.);
#703=ORIENTED_EDGE('',*,*,#702,.F.);
#704=ORIENTED_EDGE('',*,*,#532,.T.);
#705=EDGE_LOOP('',(#695,#696,#697,#703,#704));
#706=FACE_BOUND('',#705,.T.);
#707=ADVANCED_FACE('F384',(#706),#694,.F.);
#708=CARTESIAN_POINT('',(32.,0.,-9.99999999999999));
#709=DIRECTION('',(0.,0.,1.));
#710=DIRECTION('',(1.,0.,0.));
#711=AXIS2_PLACEMENT_3D('',#708,#709,#710);
#712=PLANE('',#711);
#713=DIRECTION('',(0.,-1.,0.));
#714=VECTOR('',#713,1.);
#715=CARTESIAN_POINT('',(3.99999999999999,-2.,-10.));
#716=LINE('',#715,#714);
#717=CARTESIAN_POINT('',(4.,-2.,-9.99999999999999));
#718=VERTEX_POINT('',#717);
#719=CARTESIAN_POINT('',(4.,-7.,-10.));
#720=VERTEX_POINT('',#719);
#721=EDGE_CURVE('E54',#718,#720,#716,.T.);
#722=ORIENTED_EDGE('',*,*,#721,.T.);
#723=DIRECTION('',(1.,0.,0.));
#724=VECTOR('',#723,1.);
#725=CARTESIAN_POINT('',(7.99999999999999,-7.,-9.99999999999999));
#726=LINE('',#725,#724);
#727=EDGE_CURVE('E205',#720,#29,#726,.T.);
#728=ORIENTED_EDGE('',*,*,#727,.T.);
#729=ORIENTED_EDGE('',*,*,#32,.T.);
#730=ORIENTED_EDGE('',*,*,#131,.T.);
#731=ORIENTED_EDGE('',*,*,#80,.T.);
#732=ORIENTED_EDGE('',*,*,#569,.T.);
#733=ORIENTED_EDGE('',*,*,#540,.T.);
#734=ORIENTED_EDGE('',*,*,#702,.T.);
#735=ORIENTED_EDGE('',*,*,#213,.T.);
#736=ORIENTED_EDGE('',*,*,#182,.T.);
#737=ORIENTED_EDGE('',*,*,#159,.T.);
#738=DIRECTION('',(-1.,0.,0.));
#739=VECTOR('',#738,1.);
#740=CARTESIAN_POINT('',(7.99999999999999,-2.,-9.99999999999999));
#741=LINE('',#740,#739);
#742=EDGE_CURVE('E186',#154,#718,#741,.T.);
#743=ORIENTED_EDGE('',*,*,#742,.T.);
#744=EDGE_LOOP('',(#722,#728,#729,#730,#731,#732,#733,#734,#735,#736,#737,#743));
#745=FACE_BOUND('',#744,.T.);
#746=ADVANCED_FACE('F207',(#745),#712,.F.);
#747=CARTESIAN_POINT('',(-29.0654558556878,13.,22.));
#748=DIRECTION('',(0.,0.,1.));
#749=DIRECTION('',(1.,0.,0.));
#750=AXIS2_PLACEMENT_3D('',#747,#748,#749);
#751=CYLINDRICAL_SURFACE('',#750,3.);
#752=ORIENTED_EDGE('',*,*,#627,.F.);
#753=ORIENTED_EDGE('',*,*,#460,.F.);
#754=ORIENTED_EDGE('',*,*,#660,.F.);
#755=ORIENTED_EDGE('',*,*,#493,.F.);
#756=EDGE_LOOP('',(#752,#753,#754,#755));
#757=FACE_BOUND('',#756,.T.);
#758=ADVANCED_FACE('F421',(#757),#751,.F.);
#759=CARTESIAN_POINT('',(29.0654558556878,13.,22.));
#760=DIRECTION('',(0.,0.,1.));
#761=DIRECTION('',(1.,0.,0.));
#762=AXIS2_PLACEMENT_3D('',#759,#760,#761);
#763=CYLINDRICAL_SURFACE('',#762,3.);
#764=ORIENTED_EDGE('',*,*,#617,.F.);
#765=ORIENTED_EDGE('',*,*,#267,.F.);
#766=ORIENTED_EDGE('',*,*,#680,.F.);
#767=ORIENTED_EDGE('',*,*,#300,.F.);
#768=EDGE_LOOP('',(#764,#765,#766,#767));
#769=FACE_BOUND('',#768,.T.);
#770=ADVANCED_FACE('F36',(#769),#763,.F.);
#771=CARTESIAN_POINT('',(0.,20.,-2.));
#772=DIRECTION('',(0.,0.,1.));
#773=DIRECTION('',(1.,0.,0.));
#774=AXIS2_PLACEMENT_3D('',#771,#772,#773);
#775=CYLINDRICAL_SURFACE('',#774,6.);
#776=CARTESIAN_POINT('',(0.,26.,13.));
#777=CARTESIAN_POINT('',(0.0788941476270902,25.9999993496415,12.9999991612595));
#778=CARTESIAN_POINT('',(0.15779662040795,25.9984386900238,12.9968820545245));
#779=CARTESIAN_POINT('',(0.315001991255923,25.9922435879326,12.98446072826));
#780=CARTESIAN_POINT('',(0.393304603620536,25.987607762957,12.9751537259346));
#781=CARTESIAN_POINT('',(0.626628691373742,25.9692197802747,12.9380421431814));
#782=CARTESIAN_POINT('',(0.779952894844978,25.950987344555,12.9010471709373));
#783=CARTESIAN_POINT('',(1.07683586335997,25.9044896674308,12.8044182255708));
#784=CARTESIAN_POINT('',(1.22043005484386,25.8762634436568,12.7448722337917));
#785=CARTESIAN_POINT('',(1.49540820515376,25.8123730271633,12.6052887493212));
#786=CARTESIAN_POINT('',(1.62679312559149,25.7767094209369,12.5252528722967));
#787=CARTESIAN_POINT('',(1.88252701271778,25.6986875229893,12.3414460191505));
#788=CARTESIAN_POINT('',(2.0059694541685,25.6560547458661,12.2365320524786));
#789=CARTESIAN_POINT('',(2.23433451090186,25.5698003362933,12.0084440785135));
#790=CARTESIAN_POINT('',(2.33924301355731,25.5261779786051,11.8852562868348));
#791=CARTESIAN_POINT('',(2.53576864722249,25.4389634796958,11.6125156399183));
#792=CARTESIAN_POINT('',(2.62572411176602,25.3956360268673,11.4616590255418));
#793=CARTESIAN_POINT('',(2.74034031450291,25.3378244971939,11.2240491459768));
#794=CARTESIAN_POINT('',(2.77516786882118,25.3197457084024,11.1429290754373));
#795=CARTESIAN_POINT('',(2.83769299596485,25.2866576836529,10.9773994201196));
#796=CARTESIAN_POINT('',(2.86539478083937,25.2716466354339,10.8929918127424));
#797=CARTESIAN_POINT('',(2.91188280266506,25.2461034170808,10.7266042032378));
#798=CARTESIAN_POINT('',(2.93110042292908,25.235358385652,10.6447772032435));
#799=CARTESIAN_POINT('',(2.96263559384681,25.2175778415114,10.4794450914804));
#800=CARTESIAN_POINT('',(2.9749568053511,25.2105403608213,10.3959408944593));
#801=CARTESIAN_POINT('',(2.99251382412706,25.2004775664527,10.2279936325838));
#802=CARTESIAN_POINT('',(2.99775389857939,25.1974498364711,10.1435511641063));
#803=CARTESIAN_POINT('',(3.00108452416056,25.1955255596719,9.97450634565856));
#804=CARTESIAN_POINT('',(2.99917575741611,25.1966286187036,9.88990401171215));
#805=CARTESIAN_POINT('',(2.98404973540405,25.2053466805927,9.65724610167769));
#806=CARTESIAN_POINT('',(2.96335042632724,25.2172679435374,9.50975584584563));
#807=CARTESIAN_POINT('',(2.90082280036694,25.2522818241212,9.22080632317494));
#808=CARTESIAN_POINT('',(2.85898775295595,25.2753780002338,9.07934899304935));
#809=CARTESIAN_POINT('',(2.75462843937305,25.3306256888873,8.80232034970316));
#810=CARTESIAN_POINT('',(2.69164495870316,25.36297559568,8.66696288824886));
#811=CARTESIAN_POINT('',(2.54712530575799,25.4331017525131,8.40809503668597));
#812=CARTESIAN_POINT('',(2.46558080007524,25.4708804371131,8.28459000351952));
#813=CARTESIAN_POINT('',(2.27419808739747,25.5533948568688,8.03643690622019));
#814=CARTESIAN_POINT('',(2.16208335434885,25.5984053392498,7.9136295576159));
#815=CARTESIAN_POINT('',(1.91866675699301,25.6864286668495,7.68779356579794));
#816=CARTESIAN_POINT('',(1.78735577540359,25.7294405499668,7.58477437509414));
#817=CARTESIAN_POINT('',(1.50154951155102,25.8110596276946,7.39694306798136));
#818=CARTESIAN_POINT('',(1.3462607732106,25.8493695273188,7.31319859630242));
#819=CARTESIAN_POINT('',(1.02139864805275,25.9147364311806,7.17370889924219));
#820=CARTESIAN_POINT('',(0.851836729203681,25.9418023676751,7.11794144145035));
#821=CARTESIAN_POINT('',(0.518299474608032,25.9797300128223,7.04057379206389));
#822=CARTESIAN_POINT('',(0.355024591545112,25.9917481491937,7.01652629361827));
#823=CARTESIAN_POINT('',(0.0263387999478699,26.0021904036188,6.99560580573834));
#824=CARTESIAN_POINT('',(-0.139071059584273,26.0006209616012,6.99871994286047));
#825=CARTESIAN_POINT('',(-0.453698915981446,25.9847357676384,7.0306200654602));
#826=CARTESIAN_POINT('',(-0.60317822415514,25.9714173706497,7.05739759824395));
#827=CARTESIAN_POINT('',(-0.895220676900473,25.9346651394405,7.1327142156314));
#828=CARTESIAN_POINT('',(-1.03778305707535,25.911230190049,7.18125569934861));
#829=CARTESIAN_POINT('',(-1.31666582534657,25.8555275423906,7.2999953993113));
#830=CARTESIAN_POINT('',(-1.45269119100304,25.8230264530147,7.37077315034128));
#831=CARTESIAN_POINT('',(-1.71138408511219,25.7523192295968,7.53132260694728));
#832=CARTESIAN_POINT('',(-1.83404588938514,25.7141106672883,7.62110240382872));
#833=CARTESIAN_POINT('',(-2.07530306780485,25.6312466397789,7.82728127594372));
#834=CARTESIAN_POINT('',(-2.19231623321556,25.5863265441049,7.94542860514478));
#835=CARTESIAN_POINT('',(-2.40556896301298,25.497871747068,8.1997754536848));
#836=CARTESIAN_POINT('',(-2.50179415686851,25.4543380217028,8.3359873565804));
#837=CARTESIAN_POINT('',(-2.675123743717,25.3715357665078,8.63093096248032));
#838=CARTESIAN_POINT('',(-2.75107648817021,25.3325758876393,8.79043379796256));
#839=CARTESIAN_POINT('',(-2.87424847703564,25.2672221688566,9.12253020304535));
#840=CARTESIAN_POINT('',(-2.92150474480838,25.2408121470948,9.29510658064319));
#841=CARTESIAN_POINT('',(-2.98158506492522,25.2068450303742,9.63073066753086));
#842=CARTESIAN_POINT('',(-2.99727899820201,25.1977215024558,9.79310275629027));
#843=CARTESIAN_POINT('',(-3.00206745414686,25.1949606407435,10.1183412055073));
#844=CARTESIAN_POINT('',(-2.99117350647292,25.2013165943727,10.2812073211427));
#845=CARTESIAN_POINT('',(-2.94577840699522,25.227135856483,10.5864504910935));
#846=CARTESIAN_POINT('',(-2.91362505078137,25.2452928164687,10.7293013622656));
#847=CARTESIAN_POINT('',(-2.8295259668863,25.2911305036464,11.0074244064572));
#848=CARTESIAN_POINT('',(-2.77757387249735,25.3188142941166,11.142694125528));
#849=CARTESIAN_POINT('',(-2.65144766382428,25.3828558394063,11.4118743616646));
#850=CARTESIAN_POINT('',(-2.57601505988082,25.4196713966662,11.5450829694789));
#851=CARTESIAN_POINT('',(-2.4064512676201,25.4970602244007,11.7978243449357));
#852=CARTESIAN_POINT('',(-2.3123103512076,25.5376354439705,11.9173499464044));
#853=CARTESIAN_POINT('',(-2.09461689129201,25.6238685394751,12.1544228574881));
#854=CARTESIAN_POINT('',(-1.9688805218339,25.6695449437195,12.2699651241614));
#855=CARTESIAN_POINT('',(-1.69843715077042,25.7563371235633,12.478801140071));
#856=CARTESIAN_POINT('',(-1.55371998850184,25.7974504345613,12.5720828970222));
#857=CARTESIAN_POINT('',(-1.32452333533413,25.8525140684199,12.6931781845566));
#858=CARTESIAN_POINT('',(-1.24575314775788,25.8698252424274,12.7305202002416));
#859=CARTESIAN_POINT('',(-1.0847972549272,25.9016884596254,12.7983616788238));
#860=CARTESIAN_POINT('',(-1.00261324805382,25.9162418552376,12.8288644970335));
#861=CARTESIAN_POINT('',(-0.835616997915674,25.9421269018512,12.8826072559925));
#862=CARTESIAN_POINT('',(-0.750810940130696,25.9534655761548,12.905863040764));
#863=CARTESIAN_POINT('',(-0.579142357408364,25.9726077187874,12.9448825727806));
#864=CARTESIAN_POINT('',(-0.492281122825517,25.9804133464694,12.9606508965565));
#865=CARTESIAN_POINT('',(-0.337824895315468,25.9908582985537,12.9816846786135));
#866=CARTESIAN_POINT('',(-0.270495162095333,25.9942803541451,12.988546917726));
#867=CARTESIAN_POINT('',(-0.135445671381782,25.9988515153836,12.9977050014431));
#868=CARTESIAN_POINT('',(-0.067725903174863,26.0000005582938,13.0000007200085));
#869=CARTESIAN_POINT('',(0.,26.,13.));
#870=B_SPLINE_CURVE_WITH_KNOTS('',3,(#776,#777,#778,#779,#780,#781,#782,#783,#784,#785,#786,
#787,#788,#789,#790,#791,#792,#793,#794,#795,#796,#797,#798,#799,#800,#801,#802,#803,#804,#805,
#806,#807,#808,#809,#810,#811,#812,#813,#814,#815,#816,#817,#818,#819,#820,#821,#822,#823,#824,
#825,#826,#827,#828,#829,#830,#831,#832,#833,#834,#835,#836,#837,#838,#839,#840,#841,#842,#843,
#844,#845,#846,#847,#848,#849,#850,#851,#852,#853,#854,#855,#856,#857,#858,#859,#860,#861,#862,
#863,#864,#865,#866,#867,#868,#869),.UNSPECIFIED.,.T.,.F.,(4,2,2,2,2,2,2,2,2,2,2,2,2,2,2,2,2,2,
2,2,2,2,2,2,2,2,2,2,2,2,2,2,2,2,2,2,2,2,2,2,2,2,2,2,2,2,4),(0.,0.236611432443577,
0.4733293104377,0.947100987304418,1.41904300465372,1.89094781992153,2.3914018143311,
2.89223525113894,3.43190833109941,3.70192714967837,3.97178599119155,4.22563720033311,
4.47935352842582,4.73291689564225,4.9864560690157,5.43238672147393,5.8784594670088,
6.33492255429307,6.7915909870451,7.3061635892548,7.82098138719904,8.35970601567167,
8.89800185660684,9.39171406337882,9.88519228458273,10.3404225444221,10.7957029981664,
11.2640010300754,11.7324988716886,12.2470036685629,12.7618630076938,13.3016558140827,
13.8407507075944,14.3280945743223,14.8152271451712,15.2559532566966,15.6968212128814,
16.1673090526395,16.6380421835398,17.1659726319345,17.694186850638,17.9605054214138,
18.2266930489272,18.4922945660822,18.7577335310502,18.9608446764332,19.1639614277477),.UNSPECIFIED.);
#871=CARTESIAN_POINT('',(0.,26.,13.));
#872=VERTEX_POINT('',#871);
#873=EDGE_CURVE('E455',#872,#872,#870,.T.);
#874=ORIENTED_EDGE('',*,*,#873,.T.);
#875=EDGE_LOOP('',(#874));
#876=FACE_BOUND('',#875,.T.);
#877=CARTESIAN_POINT('',(0.,20.,-2.));
#878=DIRECTION('',(0.,0.,1.));
#879=DIRECTION('',(1.,0.,0.));
#880=AXIS2_PLACEMENT_3D('',#877,#878,#879);
#881=CIRCLE('',#880,6.);
#882=CARTESIAN_POINT('',(6.,20.,-2.));
#883=VERTEX_POINT('',#882);
#884=EDGE_CURVE('E241',#883,#883,#881,.T.);
#885=ORIENTED_EDGE('',*,*,#884,.F.);
#886=EDGE_LOOP('',(#885));
#887=FACE_BOUND('',#886,.T.);
#888=ORIENTED_EDGE('',*,*,#644,.T.);
#889=EDGE_LOOP('',(#888));
#890=FACE_BOUND('',#889,.T.);
#891=ADVANCED_FACE('F428',(#876,#887,#890),#775,.F.);
#892=CARTESIAN_POINT('',(0.,20.,-2.));
#893=DIRECTION('',(0.,0.,1.));
#894=DIRECTION('',(1.,0.,0.));
#895=AXIS2_PLACEMENT_3D('',#892,#893,#894);
#896=PLANE('',#895);
#897=ORIENTED_EDGE('',*,*,#884,.T.);
#898=EDGE_LOOP('',(#897));
#899=FACE_BOUND('',#898,.T.);
#900=ADVANCED_FACE('F667',(#899),#896,.T.);
#901=CARTESIAN_POINT('',(0.,7.,-2.));
#902=DIRECTION('',(0.,-1.,0.));
#903=DIRECTION('',(0.,0.,-1.));
#904=AXIS2_PLACEMENT_3D('',#901,#902,#903);
#905=CONICAL_SURFACE('',#904,3.,1.02974425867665);
#906=CARTESIAN_POINT('',(0.,8.80258185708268,-2.));
#907=VERTEX_POINT('',#906);
#908=VERTEX_LOOP('',#907);
#909=FACE_BOUND('',#908,.T.);
#910=CARTESIAN_POINT('',(0.,7.,-2.));
#911=DIRECTION('',(0.,-1.,0.));
#912=DIRECTION('',(0.,0.,-1.));
#913=AXIS2_PLACEMENT_3D('',#910,#911,#912);
#914=CIRCLE('',#913,3.);
#915=CARTESIAN_POINT('',(0.,7.,-5.));
#916=VERTEX_POINT('',#915);
#917=EDGE_CURVE('E743',#916,#916,#914,.T.);
#918=ORIENTED_EDGE('',*,*,#917,.T.);
#919=EDGE_LOOP('',(#918));
#920=FACE_BOUND('',#919,.T.);
#921=ADVANCED_FACE('F677',(#909,#920),#905,.F.);
#922=CARTESIAN_POINT('',(0.,-9.,-2.));
#923=DIRECTION('',(0.,-1.,0.));
#924=DIRECTION('',(0.,0.,-1.));
#925=AXIS2_PLACEMENT_3D('',#922,#923,#924);
#926=CYLINDRICAL_SURFACE('',#925,2.99999999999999);
#927=ORIENTED_EDGE('',*,*,#917,.F.);
#928=EDGE_LOOP('',(#927));
#929=FACE_BOUND('',#928,.T.);
#930=ORIENTED_EDGE('',*,*,#122,.T.);
#931=EDGE_LOOP('',(#930));
#932=FACE_BOUND('',#931,.T.);
#933=ADVANCED_FACE('F687',(#929,#932),#926,.F.);
#934=CARTESIAN_POINT('',(0.,7.,14.));
#935=DIRECTION('',(0.,-1.,0.));
#936=DIRECTION('',(0.,0.,-1.));
#937=AXIS2_PLACEMENT_3D('',#934,#935,#936);
#938=CONICAL_SURFACE('',#937,3.,1.02974425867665);
#939=CARTESIAN_POINT('',(0.,8.80258185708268,14.));
#940=VERTEX_POINT('',#939);
#941=VERTEX_LOOP('',#940);
#942=FACE_BOUND('',#941,.T.);
#943=CARTESIAN_POINT('',(0.,7.,14.));
#944=DIRECTION('',(0.,-1.,0.));
#945=DIRECTION('',(0.,0.,-1.));
#946=AXIS2_PLACEMENT_3D('',#943,#944,#945);
#947=CIRCLE('',#946,3.);
#948=CARTESIAN_POINT('',(0.,7.,11.));
#949=VERTEX_POINT('',#948);
#950=EDGE_CURVE('E738',#949,#949,#947,.T.);
#951=ORIENTED_EDGE('',*,*,#950,.T.);
#952=EDGE_LOOP('',(#951));
#953=FACE_BOUND('',#952,.T.);
#954=ADVANCED_FACE('F697',(#942,#953),#938,.F.);
#955=CARTESIAN_POINT('',(0.,-9.,14.));
#956=DIRECTION('',(0.,-1.,0.));
#957=DIRECTION('',(0.,0.,-1.));
#958=AXIS2_PLACEMENT_3D('',#955,#956,#957);
#959=CYLINDRICAL_SURFACE('',#958,2.99999999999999);
#960=ORIENTED_EDGE('',*,*,#950,.F.);
#961=EDGE_LOOP('',(#960));
#962=FACE_BOUND('',#961,.T.);
#963=ORIENTED_EDGE('',*,*,#111,.T.);
#964=EDGE_LOOP('',(#963));
#965=FACE_BOUND('',#964,.T.);
#966=ADVANCED_FACE('F480',(#962,#965),#959,.F.);
#967=CARTESIAN_POINT('',(0.,36.,10.));
#968=DIRECTION('',(0.,1.,0.));
#969=DIRECTION('',(0.,0.,1.));
#970=AXIS2_PLACEMENT_3D('',#967,#968,#969);
#971=CYLINDRICAL_SURFACE('',#970,5.);
#972=CARTESIAN_POINT('',(0.,32.,10.));
#973=DIRECTION('',(0.,1.,0.));
#974=DIRECTION('',(0.,0.,1.));
#975=AXIS2_PLACEMENT_3D('',#972,#973,#974);
#976=CIRCLE('',#975,5.);
#977=CARTESIAN_POINT('',(0.,32.,15.));
#978=VERTEX_POINT('',#977);
#979=EDGE_CURVE('E442',#978,#978,#976,.T.);
#980=ORIENTED_EDGE('',*,*,#979,.F.);
#981=EDGE_LOOP('',(#980));
#982=FACE_BOUND('',#981,.T.);
#983=ORIENTED_EDGE('',*,*,#405,.F.);
#984=EDGE_LOOP('',(#983));
#985=FACE_BOUND('',#984,.T.);
#986=ADVANCED_FACE('F472',(#982,#985),#971,.F.);
#987=CARTESIAN_POINT('',(0.,36.,10.));
#988=DIRECTION('',(0.,1.,0.));
#989=DIRECTION('',(0.,0.,1.));
#990=AXIS2_PLACEMENT_3D('',#987,#988,#989);
#991=CYLINDRICAL_SURFACE('',#990,3.00000000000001);
#992=ORIENTED_EDGE('',*,*,#873,.F.);
#993=EDGE_LOOP('',(#992));
#994=FACE_BOUND('',#993,.T.);
#995=CARTESIAN_POINT('',(0.,32.,10.));
#996=DIRECTION('',(0.,1.,0.));
#997=DIRECTION('',(0.,0.,1.));
#998=AXIS2_PLACEMENT_3D('',#995,#996,#997);
#999=CIRCLE('',#998,3.00000000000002);
#1000=CARTESIAN_POINT('',(0.,32.,13.));
#1001=VERTEX_POINT('',#1000);
#1002=EDGE_CURVE('E446',#1001,#1001,#999,.T.);
#1003=ORIENTED_EDGE('',*,*,#1002,.T.);
#1004=EDGE_LOOP('',(#1003));
#1005=FACE_BOUND('',#1004,.T.);
#1006=ADVANCED_FACE('F467',(#994,#1005),#991,.F.);
#1007=CARTESIAN_POINT('',(3.00000000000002,32.,10.));
#1008=DIRECTION('',(0.,-1.,0.));
#1009=DIRECTION('',(0.,0.,-1.));
#1010=AXIS2_PLACEMENT_3D('',#1007,#1008,#1009);
#1011=PLANE('',#1010);
#1012=ORIENTED_EDGE('',*,*,#1002,.F.);
#1013=EDGE_LOOP('',(#1012));
#1014=FACE_BOUND('',#1013,.T.);
#1015=ORIENTED_EDGE('',*,*,#979,.T.);
#1016=EDGE_LOOP('',(#1015));
#1017=FACE_BOUND('',#1016,.T.);
#1018=ADVANCED_FACE('F471',(#1014,#1017),#1011,.F.);
#1019=CARTESIAN_POINT('',(7.99999999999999,-7.,-9.99999999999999));
#1020=DIRECTION('',(0.,-1.,0.));
#1021=DIRECTION('',(1.,0.,0.));
#1022=AXIS2_PLACEMENT_3D('',#1019,#1020,#1021);
#1023=PLANE('',#1022);
#1024=ORIENTED_EDGE('',*,*,#592,.T.);
#1025=ORIENTED_EDGE('',*,*,#40,.F.);
#1026=ORIENTED_EDGE('',*,*,#727,.F.);
#1027=DIRECTION('',(0.,0.,1.));
#1028=VECTOR('',#1027,1.);
#1029=CARTESIAN_POINT('',(4.,-7.,-10.));
#1030=LINE('',#1029,#1028);
#1031=EDGE_CURVE('E443',#720,#591,#1030,.T.);
#1032=ORIENTED_EDGE('',*,*,#1031,.T.);
#1033=EDGE_LOOP('',(#1024,#1025,#1026,#1032));
#1034=FACE_BOUND('',#1033,.T.);
#1035=ADVANCED_FACE('F475',(#1034),#1023,.F.);
#1036=CARTESIAN_POINT('',(3.99999999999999,-2.,-10.));
#1037=DIRECTION('',(-1.,0.,0.));
#1038=DIRECTION('',(0.,-1.,0.));
#1039=AXIS2_PLACEMENT_3D('',#1036,#1037,#1038);
#1040=PLANE('',#1039);
#1041=ORIENTED_EDGE('',*,*,#600,.T.);
#1042=ORIENTED_EDGE('',*,*,#1031,.F.);
#1043=ORIENTED_EDGE('',*,*,#721,.F.);
#1044=DIRECTION('',(0.,0.,1.));
#1045=VECTOR('',#1044,1.);
#1046=CARTESIAN_POINT('',(3.99999999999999,-2.,-10.));
#1047=LINE('',#1046,#1045);
#1048=EDGE_CURVE('E192',#718,#599,#1047,.T.);
#1049=ORIENTED_EDGE('',*,*,#1048,.T.);
#1050=EDGE_LOOP('',(#1041,#1042,#1043,#1049));
#1051=FACE_BOUND('',#1050,.T.);
#1052=ADVANCED_FACE('F484',(#1051),#1040,.F.);
#1053=CARTESIAN_POINT('',(7.99999999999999,-2.,-9.99999999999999));
#1054=DIRECTION('',(0.,1.,0.));
#1055=DIRECTION('',(-1.,0.,0.));
#1056=AXIS2_PLACEMENT_3D('',#1053,#1054,#1055);
#1057=PLANE('',#1056);
#1058=ORIENTED_EDGE('',*,*,#606,.T.);
#1059=ORIENTED_EDGE('',*,*,#1048,.F.);
#1060=ORIENTED_EDGE('',*,*,#742,.F.);
#1061=ORIENTED_EDGE('',*,*,#155,.T.);
#1062=EDGE_LOOP('',(#1058,#1059,#1060,#1061));
#1063=FACE_BOUND('',#1062,.T.);
#1064=ADVANCED_FACE('F189',(#1063),#1057,.F.);
#1065=CLOSED_SHELL('',(#58,#98,#142,#169,#200,#247,#278,#318,#440,#471,#511,#558,#580,#648,#673,
#689,#707,#746,#758,#770,#891,#900,#921,#933,#954,#966,#986,#1006,#1018,#1035,#1052,#1064));
#1066=MANIFOLD_SOLID_BREP('B2',#1065);
#1067=ADVANCED_BREP_SHAPE_REPRESENTATION('',(#18,#1066),#14);
#1068=SHAPE_DEFINITION_REPRESENTATION(#9,#1067);
ENDSEC;
END-ISO-10303-21;
